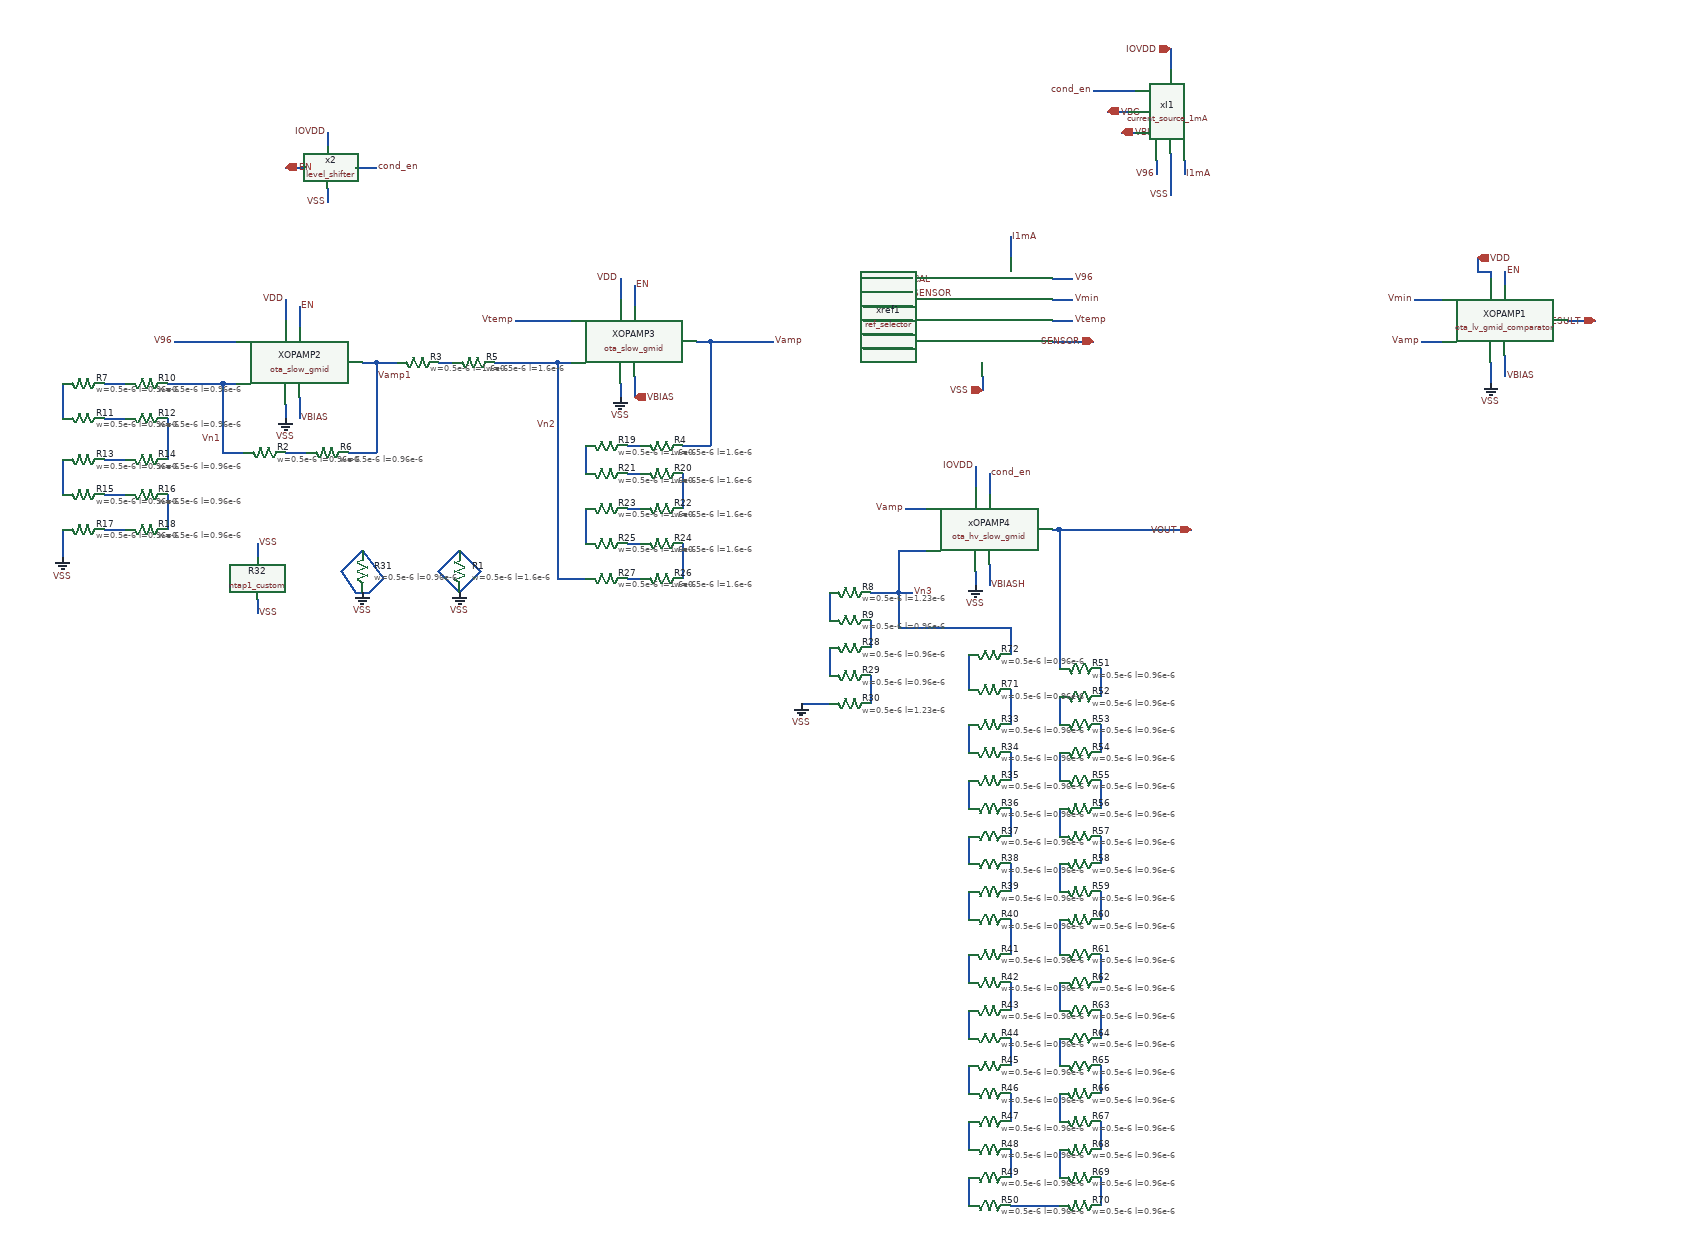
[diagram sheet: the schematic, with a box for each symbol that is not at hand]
v {xschem version=3.4.8RC file_version=1.3}
G {}
K {}
V {}
S {}
F {}
E {}
N -360 210 -360 240 {lab=VBIAS}
N -380 220 -380 240 {lab=VSS}
N -360 80 -360 110 {lab=EN}
N -470 190 -450 190 {lab=Vn2}
N -270 160 -250 160 {lab=Vamp}
N -840 240 -840 270 {lab=VBIAS}
N -860 250 -860 270 {lab=VSS}
N -840 110 -840 140 {lab=EN}
N -950 220 -930 220 {lab=Vn1}
N -950 220 -950 320 {lab=Vn1}
N 150 480 150 510 {lab=VBIASH}
N 130 490 130 510 {lab=VSS}
N 150 350 150 380 {lab=cond_en}
N 20 460 60 460 {lab=Vn3}
N -470 190 -470 500 {lab=Vn2}
N -530 130 -450 130 {lab=Vtemp}
N -1020 160 -930 160 {lab=V96}
N -730 190 -730 320 {lab=Vamp1}
N -750 190 -730 190 {lab=Vamp1}
N -560 190 -470 190 {lab=Vn2}
N 30 400 60 400 {lab=Vamp}
N -250 160 -250 310 {lab=Vamp}
N -250 160 -160 160 {lab=Vamp}
N -30 130 40 130 {lab=S1}
N -30 150 40 150 {lab=S2}
N -30 170 40 170 {lab=S3}
N -30 110 40 110 {lab=S0}
N 140 210 140 230 {lab=VSS}
N 240 70 270 70 {lab=V96}
N 240 100 270 100 {lab=Vmin}
N 240 130 270 130 {lab=Vtemp}
N -10 70 40 70 {lab=SEL_CAL}
N 240 160 300 160 {lab=SENSOR}
N -10 90 40 90 {lab=SEL_SENSOR}
N 180 10 180 40 {lab=I1mA}
N 850 40 850 60 {lab=VDD}
N 770 160 800 160 {lab=Vamp}
N 760 100 800 100 {lab=Vmin}
N 980 130 1020 130 {lab=CMP_RESULT}
N 870 60 870 70 {lab=VDD}
N 850 60 870 60 {lab=VDD}
N 870 190 870 220 {lab=VSS}
N 890 180 890 210 {lab=VBIAS}
N 890 60 890 80 {lab=EN}
N 130 340 130 370 {lab=IOVDD}
N 340 -140 360 -140 {lab=VBIASH}
N 410 -260 410 -230 {lab=IOVDD}
N 410 -110 410 -50 {lab=VSS}
N 390 -100 390 -80 {lab=V96}
N 430 -100 430 -80 {lab=I1mA}
N 320 -170 350 -170 {lab=VBG}
N -800 -140 -800 -120 {lab=IOVDD}
N -800 -60 -800 -40 {lab=VSS}
N 300 -200 360 -200 {lab=cond_en}
N -860 -90 -830 -90 {lab=EN}
N -760 -90 -730 -90 {lab=cond_en}
N -380 70 -380 100 {lab=VDD}
N -860 100 -860 130 {lab=VDD}
N -770 320 -730 320 {lab=Vamp1}
N -860 320 -830 320 {lab=#net1}
N -950 320 -920 320 {lab=Vn1}
N -1120 220 -1090 220 {lab=#net2}
N -1120 270 -1090 270 {lab=#net3}
N -1120 330 -1090 330 {lab=#net4}
N -1120 380 -1090 380 {lab=#net5}
N -1120 430 -1090 430 {lab=#net6}
N -1180 220 -1180 270 {lab=#net7}
N -1030 270 -1030 330 {lab=#net8}
N -1180 330 -1180 380 {lab=#net9}
N -1030 380 -1030 430 {lab=#net10}
N -1180 430 -1180 470 {lab=VSS}
N -1030 220 -950 220 {lab=Vn1}
N -640 190 -620 190 {lab=#net11}
N -730 190 -700 190 {lab=Vamp1}
N -370 310 -350 310 {lab=#net12}
N -370 350 -350 350 {lab=#net13}
N -370 400 -350 400 {lab=#net14}
N -370 450 -350 450 {lab=#net15}
N -370 500 -350 500 {lab=#net16}
N -430 310 -430 350 {lab=#net17}
N -290 350 -290 400 {lab=#net18}
N -430 400 -430 450 {lab=#net19}
N -290 450 -290 500 {lab=#net20}
N -470 500 -430 500 {lab=Vn2}
N -290 310 -250 310 {lab=Vamp}
N 250 430 440 430 {lab=VOUT}
N -640 490 -610 460 {lab=VSS}
N -640 490 -610 520 {lab=VSS}
N -610 520 -580 490 {lab=VSS}
N -610 460 -580 490 {lab=VSS}
N -780 490 -750 460 {lab=VSS}
N -780 490 -760 520 {lab=VSS}
N -760 520 -740 520 {lab=VSS}
N -740 520 -720 500 {lab=VSS}
N -750 460 -720 500 {lab=VSS}
N -900 530 -900 550 {lab=VSS}
N -900 450 -900 470 {lab=VSS}
N 20 520 40 520 {lab=Vn3}
N -20 520 20 520 {lab=Vn3}
N -80 520 -80 560 {lab=#net21}
N -20 560 -20 600 {lab=#net22}
N -80 600 -80 640 {lab=#net23}
N -20 640 -20 680 {lab=#net24}
N -120 680 -80 680 {lab=VSS}
N 120 710 120 750 {lab=#net25}
N 180 750 180 790 {lab=#net26}
N 180 830 180 870 {lab=#net27}
N 120 870 120 910 {lab=#net28}
N 180 910 180 950 {lab=#net29}
N 120 950 120 990 {lab=#net30}
N 120 790 120 830 {lab=#net31}
N 120 1040 120 1080 {lab=#net32}
N 180 1080 180 1120 {lab=#net33}
N 120 1120 120 1160 {lab=#net34}
N 180 1160 180 1200 {lab=#net35}
N 180 1240 180 1280 {lab=#net36}
N 120 1280 120 1320 {lab=#net37}
N 180 1320 180 1360 {lab=#net38}
N 120 1360 120 1400 {lab=#net39}
N 120 1200 120 1240 {lab=#net40}
N 180 990 180 1040 {lab=#net41}
N 310 630 310 670 {lab=#net42}
N 250 670 250 710 {lab=#net43}
N 310 710 310 750 {lab=#net44}
N 250 750 250 790 {lab=#net45}
N 250 830 250 870 {lab=#net46}
N 310 870 310 910 {lab=#net47}
N 250 910 250 950 {lab=#net48}
N 310 950 310 990 {lab=#net49}
N 310 790 310 830 {lab=#net50}
N 310 1040 310 1080 {lab=#net51}
N 250 1080 250 1120 {lab=#net52}
N 310 1120 310 1160 {lab=#net53}
N 250 1160 250 1200 {lab=#net54}
N 250 1240 250 1280 {lab=#net55}
N 310 1280 310 1320 {lab=#net56}
N 250 1320 250 1360 {lab=#net57}
N 310 1360 310 1400 {lab=#net58}
N 310 1200 310 1240 {lab=#net59}
N 250 990 250 1040 {lab=#net60}
N 180 1400 250 1400 {lab=#net61}
N 180 660 180 710 {lab=#net62}
N 120 610 120 660 {lab=#net63}
N 180 570 180 610 {lab=Vn3}
N 20 570 180 570 {lab=Vn3}
N 20 520 20 570 {lab=Vn3}
N 250 430 250 630 {lab=VOUT}
N 240 430 250 430 {lab=VOUT}
N 20 460 20 520 {lab=Vn3}
C {lab_pin.sym} -160 160 0 1 {name=p18 sig_type=std_logic lab=Vamp}
C {iopin.sym} -360 240 2 1 {name=p12 sig_type=std_logic lab=VBIAS}
C {lab_pin.sym} -380 70 0 0 {name=p24 sig_type=std_logic lab=VDD}
C {gnd.sym} -380 240 0 0 {name=l4 lab=VSS}
C {lab_pin.sym} -840 270 2 0 {name=p8 sig_type=std_logic lab=VBIAS}
C {gnd.sym} -860 270 0 0 {name=l3 lab=VSS}
C {lab_pin.sym} -860 100 0 0 {name=p10 sig_type=std_logic lab=VDD}
C {lab_pin.sym} -530 130 0 0 {name=p11 sig_type=std_logic lab=Vtemp}
C {lab_pin.sym} -1020 160 0 0 {name=p13 sig_type=std_logic lab=V96}
C {lab_pin.sym} 150 510 2 0 {name=p20 sig_type=std_logic lab=VBIASH}
C {gnd.sym} 130 510 0 0 {name=l11 lab=VSS}
C {lab_pin.sym} 130 340 0 0 {name=p23 sig_type=std_logic lab=IOVDD}
C {gnd.sym} -1180 470 0 0 {name=l5 lab=VSS}
C {lab_pin.sym} 30 400 0 0 {name=p14 sig_type=std_logic lab=Vamp}
C {lab_pin.sym} -730 210 0 1 {name=p15 sig_type=std_logic lab=Vamp1}
C {lab_pin.sym} -470 280 0 0 {name=p16 sig_type=std_logic lab=Vn2}
C {lab_pin.sym} -950 300 0 0 {name=p17 sig_type=std_logic lab=Vn1}
C {iopin.sym} 440 430 0 0 {name=p19 sig_type=std_logic lab=VOUT
}
C {iopin.sym} 10 110 0 1 {name=p32 lab=S0}
C {iopin.sym} 10 130 0 1 {name=p33 lab=S1}
C {iopin.sym} 10 150 0 1 {name=p34 lab=S2}
C {iopin.sym} 10 170 0 1 {name=p35 lab=S3}
C {iopin.sym} 140 230 0 0 {name=p36 lab=VSS}
C {lab_pin.sym} 270 70 0 1 {name=p37 lab=V96}
C {lab_pin.sym} 270 100 0 1 {name=p38 lab=Vmin}
C {lab_pin.sym} 270 130 0 1 {name=p39 lab=Vtemp}
C {iopin.sym} -10 90 0 1 {name=p46 lab=SEL_SENSOR}
C {iopin.sym} -10 70 0 1 {name=p47 lab=SEL_CAL}
C {gnd.sym} 870 220 0 0 {name=l8 lab=VSS}
C {iopin.sym} 850 40 0 1 {name=p49 sig_type=std_logic lab=VDD}
C {lab_pin.sym} 770 160 0 0 {name=p50 sig_type=std_logic lab=Vamp}
C {lab_pin.sym} 760 100 0 0 {name=p51 lab=Vmin}
C {iopin.sym} 1020 130 0 0 {name=p53 lab=CMP_RESULT}
C {devices/lab_pin.sym} 890 210 2 0 {name=p68 sig_type=std_logic lab=VBIAS}
C {/foss/designs/xschemas/ota_lv_gmid_comparator.sym} 880 130 0 0 {name=XOPAMP1 nbulk=VSS}
C {/foss/designs/xschemas/ota_hv_slow_gmid.sym} 130 430 0 0 {name=xOPAMP4 nbulk=VSS}
C {iopin.sym} 340 -140 0 1 {name=p1 sig_type=std_logic lab=VBIASH}
C {iopin.sym} 410 -260 0 0 {name=p56 sig_type=std_logic lab=IOVDD}
C {lab_pin.sym} 390 -80 0 0 {name=p58 lab=V96}
C {lab_pin.sym} 410 -50 0 0 {name=p59 lab=VSS}
C {lab_pin.sym} 430 -80 0 1 {name=p60 lab=I1mA}
C {lab_pin.sym} 180 10 0 1 {name=p61 lab=I1mA}
C {iopin.sym} 320 -170 0 1 {name=p63 sig_type=std_logic lab=VBG}
C {/foss/designs/xschemas/current_source_1mA.sym} 410 -170 0 0 {name=xI1 nbulk=VSS}
C {/foss/designs/xschemas/level_shifter.sym} -800 -90 0 0 {name=x2}
C {lab_pin.sym} -800 -140 0 0 {name=p57 sig_type=std_logic lab=IOVDD}
C {lab_pin.sym} -800 -40 0 0 {name=p64 lab=VSS}
C {iopin.sym} -860 -90 0 1 {name=p65 lab=EN}
C {lab_pin.sym} -730 -90 0 1 {name=p45 lab=cond_en}
C {lab_pin.sym} 300 -200 0 0 {name=p66 lab=cond_en}
C {lab_pin.sym} 150 350 0 1 {name=p67 lab=cond_en}
C {lab_pin.sym} 890 60 0 1 {name=p55 sig_type=std_logic lab=EN}
C {lab_pin.sym} -360 80 0 1 {name=p21 lab=EN}
C {/foss/designs/xschemas/ota_slow_gmid.sym} -850 190 0 0 {name=XOPAMP2 nbulk=VSS}
C {/foss/designs/xschemas/ota_slow_gmid.sym} -370 160 0 0 {name=XOPAMP3 nbulk=VSS}
C {/foss/designs/xschemas/ref_selector.sym} 190 100 0 0 {name=xref1 nbulk=VSS}
C {sg13g2_pr/rhigh.sym} -890 320 1 0 {name=R2
w=0.5e-6
l=0.96e-6
model=rhigh
body=VSS
spiceprefix=X
b=0
m=1
}
C {sg13g2_pr/rhigh.sym} -800 320 1 0 {name=R6
w=0.5e-6
l=0.96e-6
model=rhigh
body=VSS
spiceprefix=X
b=0
m=1
}
C {sg13g2_pr/rhigh.sym} -1150 220 1 0 {name=R7
w=0.5e-6
l=0.96e-6
model=rhigh
body=VSS
spiceprefix=X
b=0
m=1
}
C {sg13g2_pr/rhigh.sym} -1060 220 1 0 {name=R10
w=0.5e-6
l=0.96e-6
model=rhigh
body=VSS
spiceprefix=X
b=0
m=1
}
C {sg13g2_pr/rhigh.sym} -1150 270 1 0 {name=R11
w=0.5e-6
l=0.96e-6
model=rhigh
body=VSS
spiceprefix=X
b=0
m=1
}
C {sg13g2_pr/rhigh.sym} -1060 270 1 0 {name=R12
w=0.5e-6
l=0.96e-6
model=rhigh
body=VSS
spiceprefix=X
b=0
m=1
}
C {sg13g2_pr/rhigh.sym} -1150 330 1 0 {name=R13
w=0.5e-6
l=0.96e-6
model=rhigh
body=VSS
spiceprefix=X
b=0
m=1
}
C {sg13g2_pr/rhigh.sym} -1060 330 1 0 {name=R14
w=0.5e-6
l=0.96e-6
model=rhigh
body=VSS
spiceprefix=X
b=0
m=1
}
C {sg13g2_pr/rhigh.sym} -1150 380 1 0 {name=R15
w=0.5e-6
l=0.96e-6
model=rhigh
body=VSS
spiceprefix=X
b=0
m=1
}
C {sg13g2_pr/rhigh.sym} -1060 380 1 0 {name=R16
w=0.5e-6
l=0.96e-6
model=rhigh
body=VSS
spiceprefix=X
b=0
m=1
}
C {sg13g2_pr/rhigh.sym} -1150 430 1 0 {name=R17
w=0.5e-6
l=0.96e-6
model=rhigh
body=VSS
spiceprefix=X
b=0
m=1
}
C {sg13g2_pr/rhigh.sym} -1060 430 1 0 {name=R18
w=0.5e-6
l=0.96e-6
model=rhigh
body=VSS
spiceprefix=X
b=0
m=1
}
C {sg13g2_pr/rhigh.sym} -590 190 1 0 {name=R5
w=0.5e-6
l=1.6e-6
model=rhigh
body=VSS
spiceprefix=X
b=0
m=1
}
C {sg13g2_pr/rhigh.sym} -670 190 1 0 {name=R3
w=0.5e-6
l=1.6e-6
model=rhigh
body=VSS
spiceprefix=X
b=0
m=1
}
C {sg13g2_pr/rhigh.sym} -320 310 1 0 {name=R4
w=0.5e-6
l=1.6e-6
model=rhigh
body=VSS
spiceprefix=X
b=0
m=1
}
C {sg13g2_pr/rhigh.sym} -400 310 1 0 {name=R19
w=0.5e-6
l=1.6e-6
model=rhigh
body=VSS
spiceprefix=X
b=0
m=1
}
C {sg13g2_pr/rhigh.sym} -320 350 1 0 {name=R20
w=0.5e-6
l=1.6e-6
model=rhigh
body=VSS
spiceprefix=X
b=0
m=1
}
C {sg13g2_pr/rhigh.sym} -400 350 1 0 {name=R21
w=0.5e-6
l=1.6e-6
model=rhigh
body=VSS
spiceprefix=X
b=0
m=1
}
C {sg13g2_pr/rhigh.sym} -320 400 1 0 {name=R22
w=0.5e-6
l=1.6e-6
model=rhigh
body=VSS
spiceprefix=X
b=0
m=1
}
C {sg13g2_pr/rhigh.sym} -400 400 1 0 {name=R23
w=0.5e-6
l=1.6e-6
model=rhigh
body=VSS
spiceprefix=X
b=0
m=1
}
C {sg13g2_pr/rhigh.sym} -320 450 1 0 {name=R24
w=0.5e-6
l=1.6e-6
model=rhigh
body=VSS
spiceprefix=X
b=0
m=1
}
C {sg13g2_pr/rhigh.sym} -400 450 1 0 {name=R25
w=0.5e-6
l=1.6e-6
model=rhigh
body=VSS
spiceprefix=X
b=0
m=1
}
C {sg13g2_pr/rhigh.sym} -320 500 1 0 {name=R26
w=0.5e-6
l=1.6e-6
model=rhigh
body=VSS
spiceprefix=X
b=0
m=1
}
C {sg13g2_pr/rhigh.sym} -400 500 1 0 {name=R27
w=0.5e-6
l=1.6e-6
model=rhigh
body=VSS
spiceprefix=X
b=0
m=1
}
C {sg13g2_pr/rhigh.sym} -610 490 2 0 {name=R1
w=0.5e-6
l=1.6e-6
model=rhigh
body=VSS
spiceprefix=X
b=0
m=6
}
C {gnd.sym} -610 520 0 0 {name=l1 lab=VSS}
C {sg13g2_pr/rhigh.sym} -750 490 0 1 {name=R31
w=0.5e-6
l=0.96e-6
model=rhigh
body=VSS
spiceprefix=X
b=0
m=16
}
C {gnd.sym} -750 520 0 0 {name=l2 lab=VSS}
C {lab_pin.sym} -900 550 0 1 {name=p25 lab=VSS}
C {lab_pin.sym} -900 450 0 1 {name=p27 lab=VSS}
C {/foss/designs/xschemas/ntap1_custom.sym} -900 500 0 0 {name=R32
model=ptap1
spiceprefix=X
w=3e-6
l=3e-6
rw=0.3e-6
A=40.755e-12
P=249.62e-6
}
C {sg13g2_pr/rhigh.sym} -50 520 1 0 {name=R8
w=0.5e-6
l=1.23e-6
model=rhigh
body=VSS
spiceprefix=X
b=0
m=1
}
C {lab_pin.sym} 40 520 0 1 {name=p69 sig_type=std_logic lab=Vn3}
C {sg13g2_pr/rhigh.sym} -50 560 1 0 {name=R9
w=0.5e-6
l=0.96e-6
model=rhigh
body=VSS
spiceprefix=X
b=0
m=1
}
C {sg13g2_pr/rhigh.sym} -50 600 1 0 {name=R28
w=0.5e-6
l=0.96e-6
model=rhigh
body=VSS
spiceprefix=X
b=0
m=1
}
C {sg13g2_pr/rhigh.sym} -50 640 1 0 {name=R29
w=0.5e-6
l=0.96e-6
model=rhigh
body=VSS
spiceprefix=X
b=0
m=1
}
C {sg13g2_pr/rhigh.sym} -50 680 1 0 {name=R30
w=0.5e-6
l=1.23e-6
model=rhigh
body=VSS
spiceprefix=X
b=0
m=1
}
C {gnd.sym} -120 680 0 0 {name=l12 lab=VSS}
C {sg13g2_pr/rhigh.sym} 150 710 1 0 {name=R33
w=0.5e-6
l=0.96e-6
model=rhigh
body=VSS
spiceprefix=X
b=0
m=1
}
C {sg13g2_pr/rhigh.sym} 150 750 1 0 {name=R34
w=0.5e-6
l=0.96e-6
model=rhigh
body=VSS
spiceprefix=X
b=0
m=1
}
C {sg13g2_pr/rhigh.sym} 150 790 1 0 {name=R35
w=0.5e-6
l=0.96e-6
model=rhigh
body=VSS
spiceprefix=X
b=0
m=1
}
C {sg13g2_pr/rhigh.sym} 150 830 3 1 {name=R36
w=0.5e-6
l=0.96e-6
model=rhigh
body=VSS
spiceprefix=X
b=0
m=1
}
C {sg13g2_pr/rhigh.sym} 150 870 3 1 {name=R37
w=0.5e-6
l=0.96e-6
model=rhigh
body=VSS
spiceprefix=X
b=0
m=1
}
C {sg13g2_pr/rhigh.sym} 150 910 3 1 {name=R38
w=0.5e-6
l=0.96e-6
model=rhigh
body=VSS
spiceprefix=X
b=0
m=1
}
C {sg13g2_pr/rhigh.sym} 150 950 3 1 {name=R39
w=0.5e-6
l=0.96e-6
model=rhigh
body=VSS
spiceprefix=X
b=0
m=1
}
C {sg13g2_pr/rhigh.sym} 150 990 3 1 {name=R40
w=0.5e-6
l=0.96e-6
model=rhigh
body=VSS
spiceprefix=X
b=0
m=1
}
C {sg13g2_pr/rhigh.sym} 150 1040 1 0 {name=R41
w=0.5e-6
l=0.96e-6
model=rhigh
body=VSS
spiceprefix=X
b=0
m=1
}
C {sg13g2_pr/rhigh.sym} 150 1080 1 0 {name=R42
w=0.5e-6
l=0.96e-6
model=rhigh
body=VSS
spiceprefix=X
b=0
m=1
}
C {sg13g2_pr/rhigh.sym} 150 1120 1 0 {name=R43
w=0.5e-6
l=0.96e-6
model=rhigh
body=VSS
spiceprefix=X
b=0
m=1
}
C {sg13g2_pr/rhigh.sym} 150 1160 1 0 {name=R44
w=0.5e-6
l=0.96e-6
model=rhigh
body=VSS
spiceprefix=X
b=0
m=1
}
C {sg13g2_pr/rhigh.sym} 150 1200 1 0 {name=R45
w=0.5e-6
l=0.96e-6
model=rhigh
body=VSS
spiceprefix=X
b=0
m=1
}
C {sg13g2_pr/rhigh.sym} 150 1240 3 1 {name=R46
w=0.5e-6
l=0.96e-6
model=rhigh
body=VSS
spiceprefix=X
b=0
m=1
}
C {sg13g2_pr/rhigh.sym} 150 1280 3 1 {name=R47
w=0.5e-6
l=0.96e-6
model=rhigh
body=VSS
spiceprefix=X
b=0
m=1
}
C {sg13g2_pr/rhigh.sym} 150 1320 3 1 {name=R48
w=0.5e-6
l=0.96e-6
model=rhigh
body=VSS
spiceprefix=X
b=0
m=1
}
C {sg13g2_pr/rhigh.sym} 150 1360 3 1 {name=R49
w=0.5e-6
l=0.96e-6
model=rhigh
body=VSS
spiceprefix=X
b=0
m=1
}
C {sg13g2_pr/rhigh.sym} 150 1400 3 1 {name=R50
w=0.5e-6
l=0.96e-6
model=rhigh
body=VSS
spiceprefix=X
b=0
m=1
}
C {sg13g2_pr/rhigh.sym} 280 630 3 1 {name=R51
w=0.5e-6
l=0.96e-6
model=rhigh
body=VSS
spiceprefix=X
b=0
m=1
}
C {sg13g2_pr/rhigh.sym} 280 670 3 1 {name=R52
w=0.5e-6
l=0.96e-6
model=rhigh
body=VSS
spiceprefix=X
b=0
m=1
}
C {sg13g2_pr/rhigh.sym} 280 710 3 1 {name=R53
w=0.5e-6
l=0.96e-6
model=rhigh
body=VSS
spiceprefix=X
b=0
m=1
}
C {sg13g2_pr/rhigh.sym} 280 750 3 1 {name=R54
w=0.5e-6
l=0.96e-6
model=rhigh
body=VSS
spiceprefix=X
b=0
m=1
}
C {sg13g2_pr/rhigh.sym} 280 790 3 1 {name=R55
w=0.5e-6
l=0.96e-6
model=rhigh
body=VSS
spiceprefix=X
b=0
m=1
}
C {sg13g2_pr/rhigh.sym} 280 830 1 0 {name=R56
w=0.5e-6
l=0.96e-6
model=rhigh
body=VSS
spiceprefix=X
b=0
m=1
}
C {sg13g2_pr/rhigh.sym} 280 870 1 0 {name=R57
w=0.5e-6
l=0.96e-6
model=rhigh
body=VSS
spiceprefix=X
b=0
m=1
}
C {sg13g2_pr/rhigh.sym} 280 910 1 0 {name=R58
w=0.5e-6
l=0.96e-6
model=rhigh
body=VSS
spiceprefix=X
b=0
m=1
}
C {sg13g2_pr/rhigh.sym} 280 950 1 0 {name=R59
w=0.5e-6
l=0.96e-6
model=rhigh
body=VSS
spiceprefix=X
b=0
m=1
}
C {sg13g2_pr/rhigh.sym} 280 990 1 0 {name=R60
w=0.5e-6
l=0.96e-6
model=rhigh
body=VSS
spiceprefix=X
b=0
m=1
}
C {sg13g2_pr/rhigh.sym} 280 1040 3 1 {name=R61
w=0.5e-6
l=0.96e-6
model=rhigh
body=VSS
spiceprefix=X
b=0
m=1
}
C {sg13g2_pr/rhigh.sym} 280 1080 3 1 {name=R62
w=0.5e-6
l=0.96e-6
model=rhigh
body=VSS
spiceprefix=X
b=0
m=1
}
C {sg13g2_pr/rhigh.sym} 280 1120 3 1 {name=R63
w=0.5e-6
l=0.96e-6
model=rhigh
body=VSS
spiceprefix=X
b=0
m=1
}
C {sg13g2_pr/rhigh.sym} 280 1160 3 1 {name=R64
w=0.5e-6
l=0.96e-6
model=rhigh
body=VSS
spiceprefix=X
b=0
m=1
}
C {sg13g2_pr/rhigh.sym} 280 1200 3 1 {name=R65
w=0.5e-6
l=0.96e-6
model=rhigh
body=VSS
spiceprefix=X
b=0
m=1
}
C {sg13g2_pr/rhigh.sym} 280 1240 1 0 {name=R66
w=0.5e-6
l=0.96e-6
model=rhigh
body=VSS
spiceprefix=X
b=0
m=1
}
C {sg13g2_pr/rhigh.sym} 280 1280 1 0 {name=R67
w=0.5e-6
l=0.96e-6
model=rhigh
body=VSS
spiceprefix=X
b=0
m=1
}
C {sg13g2_pr/rhigh.sym} 280 1320 1 0 {name=R68
w=0.5e-6
l=0.96e-6
model=rhigh
body=VSS
spiceprefix=X
b=0
m=1
}
C {sg13g2_pr/rhigh.sym} 280 1360 1 0 {name=R69
w=0.5e-6
l=0.96e-6
model=rhigh
body=VSS
spiceprefix=X
b=0
m=1
}
C {sg13g2_pr/rhigh.sym} 280 1400 1 0 {name=R70
w=0.5e-6
l=0.96e-6
model=rhigh
body=VSS
spiceprefix=X
b=0
m=1
}
C {sg13g2_pr/rhigh.sym} 150 660 1 0 {name=R71
w=0.5e-6
l=0.96e-6
model=rhigh
body=VSS
spiceprefix=X
b=0
m=1
}
C {sg13g2_pr/rhigh.sym} 150 610 1 0 {name=R72
w=0.5e-6
l=0.96e-6
model=rhigh
body=VSS
spiceprefix=X
b=0
m=1
}
C {iopin.sym} 300 160 0 0 {name=p2 lab=SENSOR}
C {lab_pin.sym} -840 110 0 1 {name=p3 lab=EN}
